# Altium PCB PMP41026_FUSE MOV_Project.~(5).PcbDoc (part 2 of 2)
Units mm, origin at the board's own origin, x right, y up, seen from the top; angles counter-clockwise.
Board outline 26.25 x 35 mm, 2 copper layers (Top Layer, Bottom Layer), stack 1.575 mm thick; 11 components, 9 nets, 22 pads, 48 vias.
Unrouted connection lines stored in the file: 1.

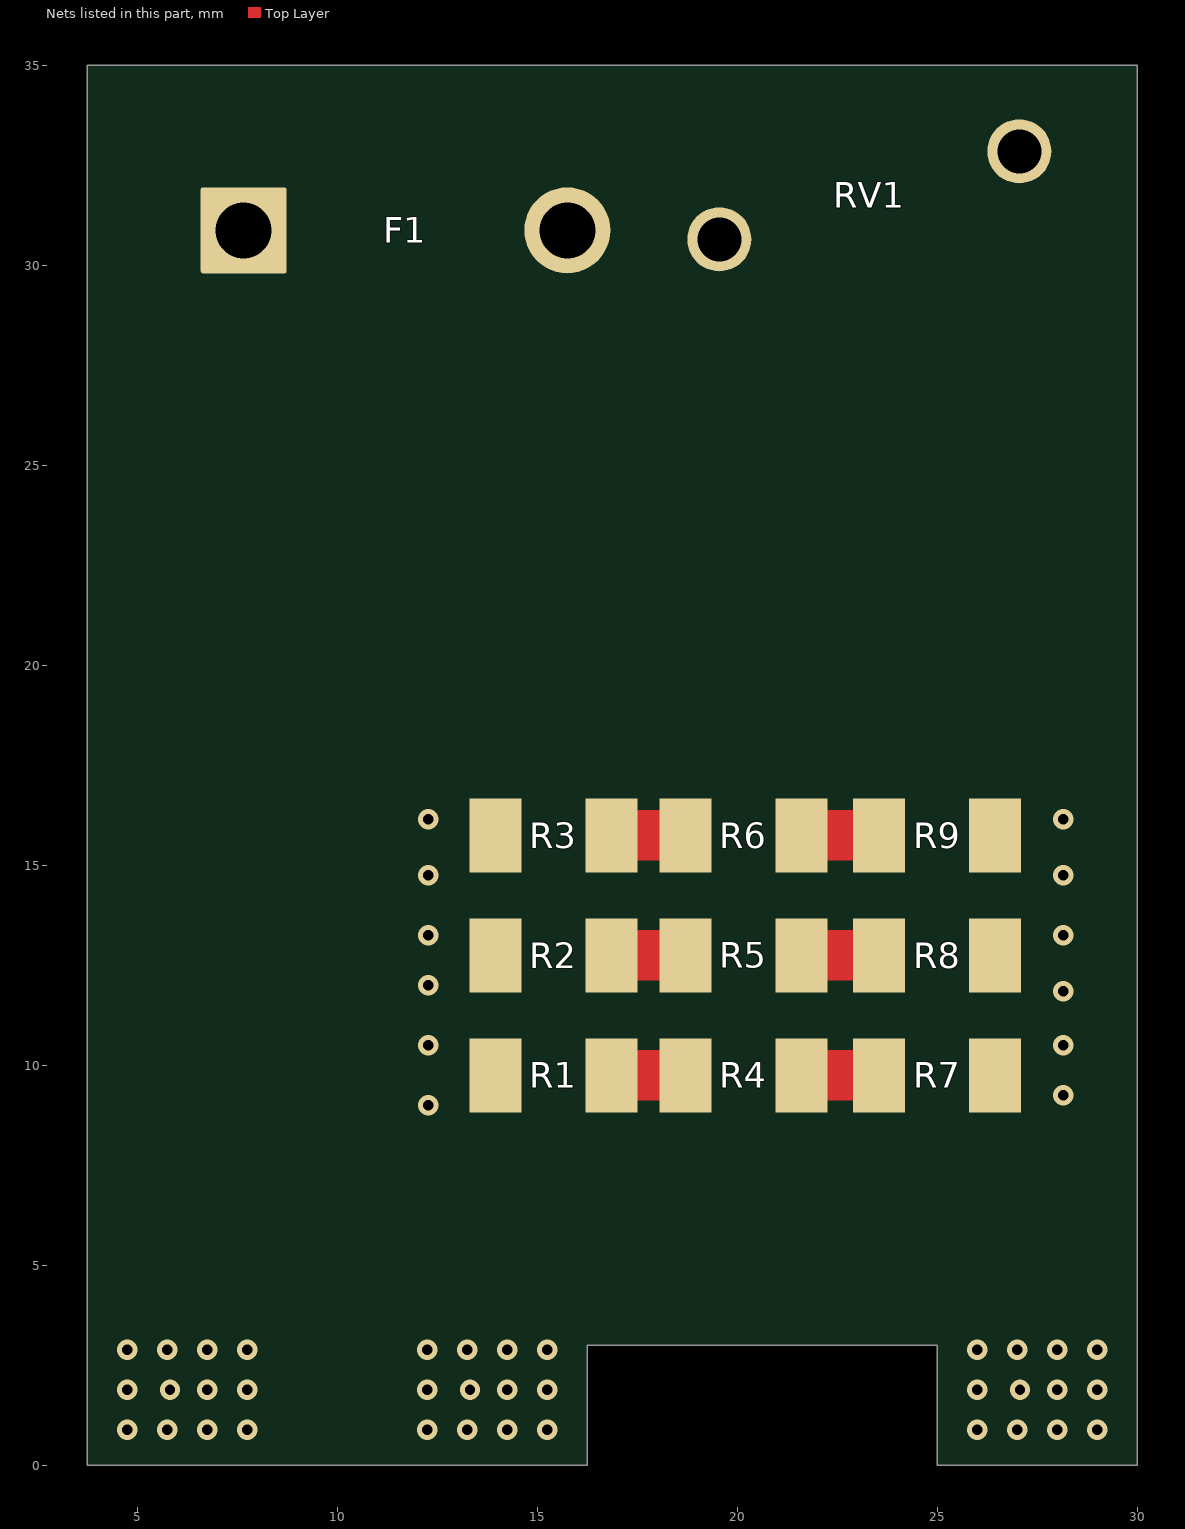
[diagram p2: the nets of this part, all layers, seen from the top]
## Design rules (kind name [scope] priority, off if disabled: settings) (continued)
PolygonConnect PolygonConnect_37 [All vs IsNamedPolygon('SGND') Or  IsNamedPolygon('SWNODE4') Or  IsNamedPolygon('5Vp') Or  IsNamedPolygon('SWNODE4') Or  IsNamedPolygon('VBB') Or  IsNamedPolygon('Line') Or  IsNamedPolygon('SGND') Or  IsNamedPolygon('SIGNAL_LAYER_2_C102_1_P032') Or  IsNamedPolygon('TOP_LAYER_54V2_P048') Or  IsNamedPolygon('ZCD') Or  IsNamedPolygon('PGND') Or  IsNamedPolygon('SIGNAL_LAYER_2_VBB_P094') Or  IsNamedPolygon('Line') Or  IsNamedPolygon('Line') Or  IsNamedPolygon('D404_2') Or  IsNamedPolygon('PGND') Or  IsNamedPolygon('SIGNAL_LAYER_1_ZCD_P108') Or  IsNamedPolygon('SWNODE3') Or  IsNamedPolygon('SIGNAL_LAYER_4_C102_1_P038') Or  IsNamedPolygon('SWNODE3') Or  IsNamedPolygon('LEG4_HS_DRV') Or  IsNamedPolygon('SWNODE4') Or  IsNamedPolygon('5Vs') Or  IsNamedPolygon('VBB') Or  IsNamedPolygon('TOP_LAYER_54V2_P048') Or  IsNamedPolygon('C102_1') Or  IsNamedPolygon('LEG4_LS_DRV') Or  IsNamedPolygon('T200_4') Or  IsNamedPolygon('SWNODE3') Or  IsNamedPolygon('Line') Or  IsNamedPolygon('SGND') Or  IsNamedPolygon('SGND') Or  IsNamedPolygon('SWNODE4') Or  IsNamedPolygon('12Vp') Or  IsNamedPolygon('BOTTOM_LAYER_NETC106_2_P030') Or  IsNamedPolygon('T200_4') Or  IsNamedPolygon('Vbulk1') Or  IsNamedPolygon('C108_1') Or  IsNamedPolygon('BOTTOM_LAYER_54V1_P128') Or  IsNamedPolygon('BOTTOM_LAYER_54V1_P128') Or  IsNamedPolygon('SWNODE') Or  IsNamedPolygon('Iout_SNS') Or  IsNamedPolygon('VSR') Or  IsNamedPolygon('D400_2') Or  IsNamedPolygon('D403_2') Or  IsNamedPolygon('SWNODE3') Or  IsNamedPolygon('T200_6') Or  IsNamedPolygon('SWNODE3') Or  IsNamedPolygon('C108_1') Or  IsNamedPolygon('PGND') Or  IsNamedPolygon('BOTTOM_LAYER_VBULK1_P096') Or  IsNamedPolygon('BOTTOM_LAYER_54V1_P128') Or  IsNamedPolygon('TOP_LAYER_12VS_P126') Or  IsNamedPolygon('SIGNAL_LAYER_1_VBULK1_P106') Or  IsNamedPolygon('T200_4') Or  IsNamedPolygon('SGND') Or  IsNamedPolygon('C108_1') Or  IsNamedPolygon('SWNODE3') Or  IsNamedPolygon('T200_6') Or  IsNamedPolygon('T200_6') Or  IsNamedPolygon('T200_6') Or  IsNamedPolygon('SGND') Or  IsNamedPolygon('C108_1') Or  IsNamedPolygon('SGND') Or  IsNamedPolygon('VBB') Or  IsNamedPolygon('T200_4') Or  IsNamedPolygon('LEG3_HS_DRV') Or  IsNamedPolygon('C108_1') Or  IsNamedPolygon('D403_2') Or  IsNamedPolygon('Iout_SNS') Or  IsNamedPolygon('C108_1') Or  IsNamedPolygon('SWNODE4')] p23: connectstyle=Direct reliefconductorwidth=0.254 reliefentries=4 polygonreliefangle="90 Angle" airgapwidth=0.254
PolygonConnect PolygonConnect_36 [All vs IsNamedPolygon('PGND') Or  IsNamedPolygon('BOTTOM_LAYER_54V1_P128') Or  IsNamedPolygon('SGND') Or  IsNamedPolygon('LEG4_LS_DRV') Or  IsNamedPolygon('TOP_LAYER_12VS_P126') Or  IsNamedPolygon('LEG4_HS_DRV') Or  IsNamedPolygon('LEG3_HS_DRV') Or  IsNamedPolygon('SGND') Or  IsNamedPolygon('C108_1') Or  IsNamedPolygon('12Vp') Or  IsNamedPolygon('D403_2') Or  IsNamedPolygon('SIGNAL_LAYER_1_ZCD_P108') Or  IsNamedPolygon('C108_1') Or  IsNamedPolygon('BOTTOM_LAYER_VBULK1_P096') Or  IsNamedPolygon('SWNODE') Or  IsNamedPolygon('T200_4') Or  IsNamedPolygon('D400_2') Or  IsNamedPolygon('C102_1') Or  IsNamedPolygon('Line') Or  IsNamedPolygon('VBB') Or  IsNamedPolygon('Line') Or  IsNamedPolygon('TOP_LAYER_54V2_P048') Or  IsNamedPolygon('BOTTOM_LAYER_NETC106_2_P030') Or  IsNamedPolygon('SIGNAL_LAYER_1_VBULK1_P106') Or  IsNamedPolygon('Line') Or  IsNamedPolygon('5Vp') Or  IsNamedPolygon('BOTTOM_LAYER_54V1_P128') Or  IsNamedPolygon('D404_2') Or  IsNamedPolygon('C108_1') Or  IsNamedPolygon('VSR') Or  IsNamedPolygon('T200_6') Or  IsNamedPolygon('VBB') Or  IsNamedPolygon('C108_1') Or  IsNamedPolygon('SIGNAL_LAYER_2_C102_1_P032') Or  IsNamedPolygon('SGND') Or  IsNamedPolygon('PGND') Or  IsNamedPolygon('SIGNAL_LAYER_4_C102_1_P038') Or  IsNamedPolygon('Vbulk1') Or  IsNamedPolygon('TOP_LAYER_54V2_P048') Or  IsNamedPolygon('Iout_SNS') Or  IsNamedPolygon('PGND') Or  IsNamedPolygon('T200_4') Or  IsNamedPolygon('ZCD') Or  IsNamedPolygon('Line') Or  IsNamedPolygon('C108_1') Or  IsNamedPolygon('D403_2') Or  IsNamedPolygon('SIGNAL_LAYER_2_VBB_P094') Or  IsNamedPolygon('SGND') Or  IsNamedPolygon('C108_1') Or  IsNamedPolygon('SIGNAL_LAYER_1_IOUT_SNS_P044') Or  IsNamedPolygon('BOTTOM_LAYER_54V1_P128') Or  IsNamedPolygon('T200_6')] p24: connectstyle=Direct reliefconductorwidth=0.254 reliefentries=4 polygonreliefangle="90 Angle" airgapwidth=0.254
PolygonConnect PolygonConnect_35 [All vs IsNamedPolygon('SWNODE') Or  IsNamedPolygon('D403_2') Or  IsNamedPolygon('D403_2') Or  IsNamedPolygon('PGND') Or  IsNamedPolygon('BOTTOM_LAYER_NETC106_2_P030') Or  IsNamedPolygon('SIGNAL_LAYER_2_C102_1_P032') Or  IsNamedPolygon('C102_1') Or  IsNamedPolygon('SIGNAL_LAYER_4_C102_1_P038') Or  IsNamedPolygon('SGND') Or  IsNamedPolygon('SIGNAL_LAYER_1_IOUT_SNS_P044') Or  IsNamedPolygon('BOTTOM_LAYER_54V1_P128') Or  IsNamedPolygon('TOP_LAYER_54V2_P048') Or  IsNamedPolygon('BOTTOM_LAYER_54V1_P128') Or  IsNamedPolygon('TOP_LAYER_54V2_P048') Or  IsNamedPolygon('C108_1') Or  IsNamedPolygon('C108_1') Or  IsNamedPolygon('C108_1') Or  IsNamedPolygon('C108_1') Or  IsNamedPolygon('C108_1') Or  IsNamedPolygon('C108_1') Or  IsNamedPolygon('PGND') Or  IsNamedPolygon('ZCD') Or  IsNamedPolygon('Line') Or  IsNamedPolygon('5Vp') Or  IsNamedPolygon('12Vp') Or  IsNamedPolygon('T200_4') Or  IsNamedPolygon('T200_6') Or  IsNamedPolygon('SGND') Or  IsNamedPolygon('T200_4') Or  IsNamedPolygon('T200_6') Or  IsNamedPolygon('SGND') Or  IsNamedPolygon('VSR') Or  IsNamedPolygon('Iout_SNS') Or  IsNamedPolygon('SIGNAL_LAYER_2_VBB_P094') Or  IsNamedPolygon('BOTTOM_LAYER_VBULK1_P096') Or  IsNamedPolygon('Vbulk1') Or  IsNamedPolygon('VBB') Or  IsNamedPolygon('SIGNAL_LAYER_1_VBULK1_P106') Or  IsNamedPolygon('SIGNAL_LAYER_1_ZCD_P108') Or  IsNamedPolygon('Line') Or  IsNamedPolygon('Line') Or  IsNamedPolygon('Line') Or  IsNamedPolygon('D404_2') Or  IsNamedPolygon('VBB') Or  IsNamedPolygon('D400_2') Or  IsNamedPolygon('SGND') Or  IsNamedPolygon('PGND') Or  IsNamedPolygon('TOP_LAYER_12VS_P126') Or  IsNamedPolygon('BOTTOM_LAYER_54V1_P128') Or  IsNamedPolygon('LEG3_HS_DRV')] p25: connectstyle=Direct reliefconductorwidth=0.254 reliefentries=4 polygonreliefangle="90 Angle" airgapwidth=0.254
PolygonConnect PolygonConnect_34 [All vs IsNamedPolygon('SWNODE') Or  IsNamedPolygon('D403_2') Or  IsNamedPolygon('D403_2') Or  IsNamedPolygon('PGND') Or  IsNamedPolygon('BOTTOM_LAYER_NETC106_2_P030') Or  IsNamedPolygon('SIGNAL_LAYER_2_C102_1_P032') Or  IsNamedPolygon('C102_1') Or  IsNamedPolygon('SIGNAL_LAYER_4_C102_1_P038') Or  IsNamedPolygon('SGND') Or  IsNamedPolygon('SIGNAL_LAYER_1_IOUT_SNS_P044') Or  IsNamedPolygon('BOTTOM_LAYER_54V1_P128') Or  IsNamedPolygon('TOP_LAYER_54V2_P048') Or  IsNamedPolygon('BOTTOM_LAYER_54V1_P128') Or  IsNamedPolygon('TOP_LAYER_54V2_P048') Or  IsNamedPolygon('C108_1') Or  IsNamedPolygon('C108_1') Or  IsNamedPolygon('C108_1') Or  IsNamedPolygon('C108_1') Or  IsNamedPolygon('C108_1') Or  IsNamedPolygon('C108_1') Or  IsNamedPolygon('PGND') Or  IsNamedPolygon('ZCD') Or  IsNamedPolygon('Line') Or  IsNamedPolygon('5Vp') Or  IsNamedPolygon('12Vp') Or  IsNamedPolygon('T200_4') Or  IsNamedPolygon('T200_6') Or  IsNamedPolygon('SGND') Or  IsNamedPolygon('T200_4') Or  IsNamedPolygon('T200_6') Or  IsNamedPolygon('SGND') Or  IsNamedPolygon('VSR') Or  IsNamedPolygon('Iout_SNS') Or  IsNamedPolygon('SIGNAL_LAYER_2_VBB_P094') Or  IsNamedPolygon('BOTTOM_LAYER_VBULK1_P096') Or  IsNamedPolygon('Vbulk1') Or  IsNamedPolygon('VBB') Or  IsNamedPolygon('SIGNAL_LAYER_1_VBULK1_P106') Or  IsNamedPolygon('SIGNAL_LAYER_1_ZCD_P108') Or  IsNamedPolygon('Line') Or  IsNamedPolygon('Line') Or  IsNamedPolygon('Line') Or  IsNamedPolygon('D404_2') Or  IsNamedPolygon('VBB') Or  IsNamedPolygon('D400_2') Or  IsNamedPolygon('SGND')] p26: connectstyle=Direct reliefconductorwidth=0.254 reliefentries=4 polygonreliefangle="90 Angle" airgapwidth=0.254
PolygonConnect PolygonConnect_33 [All vs IsNamedPolygon('SIGNAL_LAYER_1_VBULK1_P106')] p27: connectstyle=Direct reliefconductorwidth=0.254 reliefentries=4 polygonreliefangle="90 Angle" airgapwidth=0.254
PolygonConnect PolygonConnect_32 [All vs IsNamedPolygon('SIGNAL_LAYER_1_VBULK1_P106')] p28: connectstyle=Direct reliefconductorwidth=0.254 reliefentries=4 polygonreliefangle="90 Angle" airgapwidth=0.254
PolygonConnect PolygonConnect_31 [All vs IsNamedPolygon('SIGNAL_LAYER_1_VBULK1_P106')] p29: connectstyle=Direct reliefconductorwidth=0.254 reliefentries=4 polygonreliefangle="90 Angle" airgapwidth=0.254
PolygonConnect PolygonConnect_30 [All vs IsNamedPolygon('VBB')] p30: connectstyle=Direct reliefconductorwidth=0.254 reliefentries=4 polygonreliefangle="90 Angle" airgapwidth=0.254
PolygonConnect PolygonConnect_29 [All vs IsNamedPolygon('SGND')] p31: connectstyle=Direct reliefconductorwidth=0.254 reliefentries=4 polygonreliefangle="90 Angle" airgapwidth=0.254
PolygonConnect PolygonConnect_28 [All vs IsNamedPolygon('Vbulk1')] p32: connectstyle=Direct reliefconductorwidth=0.254 reliefentries=4 polygonreliefangle="90 Angle" airgapwidth=0.254
PolygonConnect PolygonConnect_27 [All vs IsNamedPolygon('BOTTOM_LAYER_VBULK1_P096')] p33: connectstyle=Direct reliefconductorwidth=0.254 reliefentries=4 polygonreliefangle="90 Angle" airgapwidth=0.254
PolygonConnect PolygonConnect_26 [All vs IsNamedPolygon('SIGNAL_LAYER_2_VBB_P094')] p34: connectstyle=Direct reliefconductorwidth=0.254 reliefentries=4 polygonreliefangle="90 Angle" airgapwidth=0.254
PolygonConnect PolygonConnect_25 [All vs IsNamedPolygon('C108_1')] p35: connectstyle=Direct reliefconductorwidth=0.254 reliefentries=4 polygonreliefangle="90 Angle" airgapwidth=0.254
PolygonConnect PolygonConnect_24 [All vs IsNamedPolygon('BOTTOM_LAYER_EARTH_P100')] p36: connectstyle=Direct reliefconductorwidth=0.254 reliefentries=4 polygonreliefangle="90 Angle" airgapwidth=0.254
PolygonConnect PolygonConnect_23 [All vs IsNamedPolygon('BOTTOM_LAYER_54V1_P128')] p37: connectstyle=Direct reliefconductorwidth=0.254 reliefentries=4 polygonreliefangle="90 Angle" airgapwidth=0.254
PolygonConnect PolygonConnect_22 [All vs IsNamedPolygon('BOTTOM_LAYER_VBULK1_P096')] p38: connectstyle=Direct reliefconductorwidth=0.254 reliefentries=4 polygonreliefangle="90 Angle" airgapwidth=0.254
PolygonConnect PolygonConnect_21 [All vs IsNamedPolygon('SIGNAL_LAYER_2_VBB_P094')] p39: connectstyle=Direct reliefconductorwidth=0.254 reliefentries=4 polygonreliefangle="90 Angle" airgapwidth=0.254
PolygonConnect PolygonConnect_20 [All vs IsNamedPolygon('Iout_SNS')] p40: connectstyle=Direct reliefconductorwidth=0.254 reliefentries=4 polygonreliefangle="90 Angle" airgapwidth=0.254
PolygonConnect PolygonConnect_19 [All vs IsNamedPolygon('C108_1') Or  IsNamedPolygon('BOTTOM_LAYER_NETC106_2_P030') Or  IsNamedPolygon('D403_2') Or  IsNamedPolygon('C102_1') Or  IsNamedPolygon('SWNODE') Or  IsNamedPolygon('D403_2') Or  IsNamedPolygon('SIGNAL_LAYER_4_C102_1_P038') Or  IsNamedPolygon('PGND') Or  IsNamedPolygon('SIGNAL_LAYER_2_C102_1_P032') Or  IsNamedPolygon('SIGNAL_LAYER_1_IOUT_SNS_P044') Or  IsNamedPolygon('SGND') Or  IsNamedPolygon('C108_1') Or  IsNamedPolygon('BOTTOM_LAYER_54V1_P128') Or  IsNamedPolygon('C108_1') Or  IsNamedPolygon('C108_1') Or  IsNamedPolygon('TOP_LAYER_54V2_P048') Or  IsNamedPolygon('BOTTOM_LAYER_54V1_P128') Or  IsNamedPolygon('TOP_LAYER_54V2_P048') Or  IsNamedPolygon('C108_1') Or  IsNamedPolygon('C108_1') Or  IsNamedPolygon('12Vp') Or  IsNamedPolygon('5Vp') Or  IsNamedPolygon('Line') Or  IsNamedPolygon('T200_4') Or  IsNamedPolygon('SGND') Or  IsNamedPolygon('VSR') Or  IsNamedPolygon('ZCD') Or  IsNamedPolygon('PGND') Or  IsNamedPolygon('T200_6') Or  IsNamedPolygon('Neutral') Or  IsNamedPolygon('T200_4') Or  IsNamedPolygon('SGND') Or  IsNamedPolygon('T200_6')] p41: connectstyle=Direct reliefconductorwidth=0.254 reliefentries=4 polygonreliefangle="90 Angle" airgapwidth=0.254
PolygonConnect PolygonConnect_18 [All vs IsNamedPolygon('SWNODE') Or  IsNamedPolygon('D403_2') Or  IsNamedPolygon('D403_2') Or  IsNamedPolygon('PGND') Or  IsNamedPolygon('BOTTOM_LAYER_NETC106_2_P030') Or  IsNamedPolygon('SIGNAL_LAYER_2_C102_1_P032') Or  IsNamedPolygon('C102_1') Or  IsNamedPolygon('SIGNAL_LAYER_4_C102_1_P038') Or  IsNamedPolygon('SGND') Or  IsNamedPolygon('SIGNAL_LAYER_1_IOUT_SNS_P044') Or  IsNamedPolygon('BOTTOM_LAYER_54V1_P128') Or  IsNamedPolygon('TOP_LAYER_54V2_P048') Or  IsNamedPolygon('BOTTOM_LAYER_54V1_P128') Or  IsNamedPolygon('TOP_LAYER_54V2_P048') Or  IsNamedPolygon('C108_1') Or  IsNamedPolygon('C108_1') Or  IsNamedPolygon('C108_1') Or  IsNamedPolygon('C108_1') Or  IsNamedPolygon('C108_1') Or  IsNamedPolygon('C108_1') Or  IsNamedPolygon('Neutral') Or  IsNamedPolygon('PGND') Or  IsNamedPolygon('ZCD') Or  IsNamedPolygon('Line') Or  IsNamedPolygon('5Vp') Or  IsNamedPolygon('12Vp') Or  IsNamedPolygon('T200_4') Or  IsNamedPolygon('T200_6') Or  IsNamedPolygon('SGND') Or  IsNamedPolygon('T200_4') Or  IsNamedPolygon('T200_6') Or  IsNamedPolygon('SGND')] p42: connectstyle=Direct reliefconductorwidth=0.254 reliefentries=4 polygonreliefangle="90 Angle" airgapwidth=0.254
PolygonConnect PolygonConnect_17 [All vs IsNamedPolygon('12Vp') Or  IsNamedPolygon('T200_4') Or  IsNamedPolygon('T200_6') Or  IsNamedPolygon('SGND') Or  IsNamedPolygon('TOP_LAYER_54V2_P048') Or  IsNamedPolygon('SIGNAL_LAYER_1_IOUT_SNS_P044') Or  IsNamedPolygon('BOTTOM_LAYER_54V1_P128') Or  IsNamedPolygon('SGND') Or  IsNamedPolygon('C102_1') Or  IsNamedPolygon('SIGNAL_LAYER_4_C102_1_P038') Or  IsNamedPolygon('Neutral') Or  IsNamedPolygon('C108_1') Or  IsNamedPolygon('C108_1') Or  IsNamedPolygon('C108_1') Or  IsNamedPolygon('BOTTOM_LAYER_54V1_P128') Or  IsNamedPolygon('TOP_LAYER_54V2_P048') Or  IsNamedPolygon('SIGNAL_LAYER_2_C102_1_P032') Or  IsNamedPolygon('SWNODE') Or  IsNamedPolygon('C108_1') Or  IsNamedPolygon('C108_1') Or  IsNamedPolygon('C108_1') Or  IsNamedPolygon('D403_2') Or  IsNamedPolygon('BOTTOM_LAYER_NETC106_2_P030') Or  IsNamedPolygon('PGND') Or  IsNamedPolygon('D403_2') Or  IsNamedPolygon('5Vp') Or  IsNamedPolygon('PGND') Or  IsNamedPolygon('ZCD') Or  IsNamedPolygon('Line')] p43: connectstyle=Direct reliefconductorwidth=0.254 reliefentries=4 polygonreliefangle="90 Angle" airgapwidth=0.254
PolygonConnect PolygonConnect_16 [All vs IsNamedPolygon('D403_2') Or  IsNamedPolygon('C102_1') Or  IsNamedPolygon('C108_1') Or  IsNamedPolygon('SWNODE') Or  IsNamedPolygon('BOTTOM_LAYER_54V1_P128') Or  IsNamedPolygon('SGND') Or  IsNamedPolygon('Line') Or  IsNamedPolygon('ZCD') Or  IsNamedPolygon('SIGNAL_LAYER_1_IOUT_SNS_P044') Or  IsNamedPolygon('Neutral') Or  IsNamedPolygon('PGND') Or  IsNamedPolygon('12Vp') Or  IsNamedPolygon('C108_1') Or  IsNamedPolygon('C108_1') Or  IsNamedPolygon('TOP_LAYER_54V2_P048') Or  IsNamedPolygon('C108_1') Or  IsNamedPolygon('TOP_LAYER_54V2_P048') Or  IsNamedPolygon('T200_4') Or  IsNamedPolygon('T200_6') Or  IsNamedPolygon('D403_2') Or  IsNamedPolygon('C108_1') Or  IsNamedPolygon('C108_1') Or  IsNamedPolygon('SIGNAL_LAYER_4_C102_1_P038') Or  IsNamedPolygon('SIGNAL_LAYER_2_C102_1_P032') Or  IsNamedPolygon('PGND') Or  IsNamedPolygon('BOTTOM_LAYER_NETC106_2_P030') Or  IsNamedPolygon('5Vp') Or  IsNamedPolygon('BOTTOM_LAYER_54V1_P128')] p44: connectstyle=Direct reliefconductorwidth=0.254 reliefentries=4 polygonreliefangle="90 Angle" airgapwidth=0.254
PolygonConnect PolygonConnect_15 [All vs IsNamedPolygon('SWNODE') Or  IsNamedPolygon('D403_2') Or  IsNamedPolygon('D403_2') Or  IsNamedPolygon('SIGNAL_LAYER_1_PGND_P018') Or  IsNamedPolygon('PGND') Or  IsNamedPolygon('BOTTOM_LAYER_NETC106_2_P030') Or  IsNamedPolygon('SIGNAL_LAYER_2_C102_1_P032') Or  IsNamedPolygon('C102_1') Or  IsNamedPolygon('SIGNAL_LAYER_4_C102_1_P038') Or  IsNamedPolygon('SGND') Or  IsNamedPolygon('SIGNAL_LAYER_1_IOUT_SNS_P044') Or  IsNamedPolygon('BOTTOM_LAYER_54V1_P128') Or  IsNamedPolygon('TOP_LAYER_54V2_P048') Or  IsNamedPolygon('BOTTOM_LAYER_54V1_P128') Or  IsNamedPolygon('TOP_LAYER_54V2_P048') Or  IsNamedPolygon('C108_1') Or  IsNamedPolygon('C108_1') Or  IsNamedPolygon('C108_1') Or  IsNamedPolygon('C108_1') Or  IsNamedPolygon('C108_1') Or  IsNamedPolygon('C108_1') Or  IsNamedPolygon('Neutral') Or  IsNamedPolygon('PGND') Or  IsNamedPolygon('ZCD') Or  IsNamedPolygon('Line') Or  IsNamedPolygon('5Vp') Or  IsNamedPolygon('12Vp')] p45: connectstyle=Direct reliefconductorwidth=0.254 reliefentries=4 polygonreliefangle="90 Angle" airgapwidth=0.254
PolygonConnect PolygonConnect_14 [All vs IsNamedPolygon('TOP_LAYER_54V2_P048') Or  IsNamedPolygon('C108_1') Or  IsNamedPolygon('C108_1') Or  IsNamedPolygon('SIGNAL_LAYER_4_C102_1_P038') Or  IsNamedPolygon('C102_1') Or  IsNamedPolygon('SIGNAL_LAYER_2_C102_1_P032') Or  IsNamedPolygon('SIGNAL_LAYER_1_PGND_P018') Or  IsNamedPolygon('SIGNAL_LAYER_1_IOUT_SNS_P044') Or  IsNamedPolygon('SGND') Or  IsNamedPolygon('C108_1') Or  IsNamedPolygon('ZCD') Or  IsNamedPolygon('PGND') Or  IsNamedPolygon('TOP_LAYER_54V2_P048') Or  IsNamedPolygon('BOTTOM_LAYER_NETC106_2_P030') Or  IsNamedPolygon('PGND') Or  IsNamedPolygon('C108_1') Or  IsNamedPolygon('C108_1') Or  IsNamedPolygon('D403_2') Or  IsNamedPolygon('Line') Or  IsNamedPolygon('C108_1') Or  IsNamedPolygon('Neutral') Or  IsNamedPolygon('SWNODE') Or  IsNamedPolygon('D403_2') Or  IsNamedPolygon('BOTTOM_LAYER_54V1_P128') Or  IsNamedPolygon('BOTTOM_LAYER_54V1_P128')] p46: connectstyle=Direct reliefconductorwidth=0.254 reliefentries=4 polygonreliefangle="90 Angle" airgapwidth=0.254
PolygonConnect PolygonConnect_13 [All vs IsNamedPolygon('PGND') Or  IsNamedPolygon('D403_2') Or  IsNamedPolygon('SIGNAL_LAYER_1_PGND_P018') Or  IsNamedPolygon('D403_2') Or  IsNamedPolygon('SWNODE') Or  IsNamedPolygon('SGND') Or  IsNamedPolygon('BOTTOM_LAYER_54V1_P128') Or  IsNamedPolygon('C108_1') Or  IsNamedPolygon('SIGNAL_LAYER_4_C102_1_P038') Or  IsNamedPolygon('C108_1') Or  IsNamedPolygon('TOP_LAYER_54V2_P048') Or  IsNamedPolygon('TOP_LAYER_54V2_P048') Or  IsNamedPolygon('C108_1') Or  IsNamedPolygon('C108_1') Or  IsNamedPolygon('C108_1') Or  IsNamedPolygon('BOTTOM_LAYER_NETC106_2_P030') Or  IsNamedPolygon('SIGNAL_LAYER_1_IOUT_SNS_P044') Or  IsNamedPolygon('C108_1') Or  IsNamedPolygon('C102_1') Or  IsNamedPolygon('SIGNAL_LAYER_2_C102_1_P032') Or  IsNamedPolygon('BOTTOM_LAYER_54V1_P128')] p47: connectstyle=Direct reliefconductorwidth=0.254 reliefentries=4 polygonreliefangle="90 Angle" airgapwidth=0.254
PolygonConnect PolygonConnect_12 [All vs IsNamedPolygon('TOP_LAYER_54V2_P048')] p48: connectstyle=Direct reliefconductorwidth=0.254 reliefentries=4 polygonreliefangle="90 Angle" airgapwidth=0.254
PolygonConnect PolygonConnect_11 [All vs IsNamedPolygon('BOTTOM_LAYER_54V1_P128')] p49: connectstyle=Direct reliefconductorwidth=0.254 reliefentries=4 polygonreliefangle="90 Angle" airgapwidth=0.254
PolygonConnect PolygonConnect_10 [All vs IsNamedPolygon('SIGNAL_LAYER_1_IOUT_SNS_P044')] p50: thpad.connectstyle=Direct thpad.reliefconductorwidth=0.254 thpad.reliefentries=4 thpad.polygonreliefangle="90 Angle" thpad.airgapwidth=0.254 smdpad.connectstyle=Relief smdpad.reliefconductorwidth=0.254 smdpad.reliefentries=4 smdpad.polygonreliefangle="90 Angle" smdpad.airgapwidth=0.254 via.connectstyle=Direct via.reliefconductorwidth=0.254 via.reliefentries=4 via.polygonreliefangle="90 Angle" via.airgapwidth=0.254
PolygonConnect PolygonConnect_9 [All vs IsNamedPolygon('SGND')] p51: thpad.connectstyle=Direct thpad.reliefconductorwidth=0.254 thpad.reliefentries=4 thpad.polygonreliefangle="90 Angle" thpad.airgapwidth=0.254 smdpad.connectstyle=Relief smdpad.reliefconductorwidth=0.254 smdpad.reliefentries=4 smdpad.polygonreliefangle="90 Angle" smdpad.airgapwidth=0.254 via.connectstyle=Direct via.reliefconductorwidth=0.254 via.reliefentries=4 via.polygonreliefangle="90 Angle" via.airgapwidth=0.254
PolygonConnect PolygonConnect_8 [All vs IsNamedPolygon('SGND')] p52: thpad.connectstyle=Direct thpad.reliefconductorwidth=0.254 thpad.reliefentries=4 thpad.polygonreliefangle="90 Angle" thpad.airgapwidth=0.254 smdpad.connectstyle=Relief smdpad.reliefconductorwidth=0.254 smdpad.reliefentries=4 smdpad.polygonreliefangle="90 Angle" smdpad.airgapwidth=0.254 via.connectstyle=Direct via.reliefconductorwidth=0.254 via.reliefentries=4 via.polygonreliefangle="90 Angle" via.airgapwidth=0.254
PolygonConnect PolygonConnect_7 [All vs IsNamedPolygon('SGND')] p53: thpad.connectstyle=Relief thpad.reliefconductorwidth=0 thpad.reliefentries=4 thpad.polygonreliefangle="90 Angle" thpad.airgapwidth=0 smdpad.connectstyle=Relief smdpad.reliefconductorwidth=0.254 smdpad.reliefentries=4 smdpad.polygonreliefangle="90 Angle" smdpad.airgapwidth=0.254 via.connectstyle=Relief via.reliefconductorwidth=0.254 via.reliefentries=4 via.polygonreliefangle="90 Angle" via.airgapwidth=0.254
PolygonConnect PolygonConnect_6 [All vs IsNamedPolygon('SGND')] p54: thpad.connectstyle=Direct thpad.reliefconductorwidth=0.254 thpad.reliefentries=4 thpad.polygonreliefangle="90 Angle" thpad.airgapwidth=0.254 smdpad.connectstyle=Relief smdpad.reliefconductorwidth=0.254 smdpad.reliefentries=4 smdpad.polygonreliefangle="90 Angle" smdpad.airgapwidth=0.254 via.connectstyle=Relief via.reliefconductorwidth=0.254 via.reliefentries=4 via.polygonreliefangle="90 Angle" via.airgapwidth=0.254
PolygonConnect PolygonConnect_5 [All vs IsNamedPolygon('SGND')] p55: thpad.connectstyle=Direct thpad.reliefconductorwidth=0.254 thpad.reliefentries=4 thpad.polygonreliefangle="90 Angle" thpad.airgapwidth=0.254 smdpad.connectstyle=Relief smdpad.reliefconductorwidth=0.254 smdpad.reliefentries=4 smdpad.polygonreliefangle="90 Angle" smdpad.airgapwidth=0.254 via.connectstyle=Relief via.reliefconductorwidth=0.254 via.reliefentries=4 via.polygonreliefangle="90 Angle" via.airgapwidth=0.254
PolygonConnect PolygonConnect_4 [All vs IsNamedPolygon('SIGNAL_LAYER_1_PGND_P018') Or  IsNamedPolygon('SWNODE') Or  IsNamedPolygon('D403_2') Or  IsNamedPolygon('SIGNAL_LAYER_4_C102_1_P038') Or  IsNamedPolygon('D403_2') Or  IsNamedPolygon('BOTTOM_LAYER_NETC106_2_P030') Or  IsNamedPolygon('C102_1') Or  IsNamedPolygon('PGND') Or  IsNamedPolygon('SIGNAL_LAYER_2_C102_1_P032')] p56: connectstyle=Direct reliefconductorwidth=0.254 reliefentries=4 polygonreliefangle="90 Angle" airgapwidth=0.254
PolygonConnect PolygonConnect_3 [All vs IsNamedPolygon('SWNODE') Or  IsNamedPolygon('D403_2') Or  IsNamedPolygon('Neutral') Or  IsNamedPolygon('C106_2') Or  IsNamedPolygon('D403_2') Or  IsNamedPolygon('Neutral') Or  IsNamedPolygon('Neutral')] p57: connectstyle=Direct reliefconductorwidth=0.254 reliefentries=4 polygonreliefangle="90 Angle" airgapwidth=0.254
PolygonConnect PolygonConnect_2 [All vs IsNamedPolygon('Neutral') Or  IsNamedPolygon('Neutral') Or  IsNamedPolygon('C106_2') Or  IsNamedPolygon('SWNODE') Or  IsNamedPolygon('Neutral')] p58: connectstyle=Direct reliefconductorwidth=0.254 reliefentries=4 polygonreliefangle="90 Angle" airgapwidth=0.254
PolygonConnect PolygonConnect_1 [All vs IsNamedPolygon('Neutral') Or  IsNamedPolygon('Neutral')] p59: connectstyle=Direct reliefconductorwidth=0.254 reliefentries=4 polygonreliefangle="90 Angle" airgapwidth=0.254
PolygonConnect [All] p60: connectstyle=Direct reliefconductorwidth=0.254 reliefentries=4 polygonreliefangle="90 Angle" airgapwidth=0.254
RoutingVias ThermalPadVias [IsVia and InAnyComponent] p1: holewidth=0.2 width=0.5 viastyle="Through Hole" minholewidth=0.2 minwidth=0.5 maxholewidth=0.33 maxwidth=0.6
RoutingVias [All] p2: holewidth=0.406 width=0.864 viastyle="Through Hole" minholewidth=0.2 minwidth=0.508 maxholewidth=1.016 maxwidth=1.651
SilkToBoardRegionClearance [Not ((IsComment or IsDesignator) And (Hide <> 'False')) and not InRegion(1000,500,4000,800)] p1:
SilkToSilkClearance SilkToSilkClearance_Pb-FreeLogo [(HasFootprint('Pb-Free_Overlay_Medium') OR HasFootprint('Pb-Free_Overlay_Small')) vs (HasFootprint('Pb-Free_Overlay_Medium') OR HasFootprint('Pb-Free_Overlay_Small'))] p1: silktosilkclearance=0
SilkToSilkClearance [All] p2: silktosilkclearance=0.102
SilkToSolderMaskClearance SilkToComponentPadClearance [(IsPad or IsFill or IsRegion) and InAnycomponent] p1: minsilkscreentomaskgap=0.127 clearancetoexposedcopper=TRUE
SilkToSolderMaskClearance "Silk to Solder Mask Opening" [All] p2: minsilkscreentomaskgap=0.102 clearancetoexposedcopper=FALSE
SolderMaskExpansion [All] p1: expansion=0.05
Width [All] p1: maxlimit=2.54 minlimit=0.152 preferedwidth=0.254 checkconnectedcopper=TRUE
13 further rules are at their usual default settings.

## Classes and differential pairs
net class N: N
net class L: Lout N

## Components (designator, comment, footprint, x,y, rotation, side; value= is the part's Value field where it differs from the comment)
F1 "0525025.MXEP_vm" FP-0525025.MXEP_vm_AXIAL-MFG 7.658,30.875 r0 bottom
R1 "CRCW1206330KJNEA" 1206 15.4,9.75 r180 top value=330k
R2 "CRCW1206330KJNEA" 1206 15.4,12.75 r180 top value=330k
R3 "CRCW1206330KJNEA" 1206 15.4,15.75 r180 top value=330k
R4 "CRCW1206330KJNEA" 1206 20.15,9.75 r180 top value=330k
R5 "CRCW1206330KJNEA" 1206 20.15,12.75 r180 top value=330k
R6 "CRCW1206330KJNEA" 1206 20.15,15.75 r180 top value=330k
R7 "CRCW1206330KJNEA" 1206 24.993,9.75 r180 top value=330k
R8 "CRCW1206330KJNEA" 1206 24.993,12.75 r180 top value=330k
R9 "CRCW1206330KJNEA" 1206 24.993,15.75 r180 top value=330k
RV1 "S10K275E2" VAR_S10K275E2 23.3,31.75 r0 bottom value=275V

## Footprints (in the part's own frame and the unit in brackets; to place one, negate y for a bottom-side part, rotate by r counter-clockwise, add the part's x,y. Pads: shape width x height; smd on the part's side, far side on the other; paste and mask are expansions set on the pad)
1206 [mm] "1206 from SM-752 data"
  rect 1.3x1.85 smd: 1(-1.45,0) 2(1.45,0)
  silkscreen extent -2.4,-1.21 2.4,1.21, body extent -1.7,-0.9 1.7,0.9, height 1.35
FP-0525025.MXEP_vm_AXIAL-MFG [mm]
  rrect5% 2.15x2.15 hole 1.4 paste-1000 mask+0: 1(0,0)
  round 2.15 hole 1.4 paste-1000 mask+0: 2(8.092,0)
  silkscreen extent -3.64,-3.64 3.64,3.64, body extent -3.49,-3.49 8.69,3.49, height 34.52
VAR_S10K275E2 [mm] "EPCOS"
  round 1.6 hole 1.1: 1(-3.75,1.1) 2(3.75,-1.1)
  silkscreen extent -6,-2.7 6,2.7, body extent -6.02,-2.7 5.98,2.7, height 15

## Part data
F1: library part CMP-4956-0000-1, "25A AC 450V DC Fuse Cartridge, Ceramic Through Hole 3AB, 3AG, 1/4\" x 1-1/4\" (Axial)", Digikey Part Number=F10249-ND, Fuse Current=25A, Fuse Interrupt Dc Current=10000A, Manufacturer=Littelfuse, Mouser Part Number=576-0525025.MXEP, Operating Temperature Range="-55°C to +125°C"
R1 R2 R3 R4 R5 R6 R7 R8 R9: library part CMP-0018656-3, "RES, 330 k, 5%, 0.25 W, AEC-Q200 Grade 0, 1206", Manufacturer=Vishay-Dale, Power_W=250mW, Supplier Part Number 1=541-330KECT-ND, TempCo="200 ppm/C", Tolerance_%=5%, Value2=0.25W, Value_Code=330k
RV1: library part CMP-0002100-2, "Varistor 275V RMS 10MM Radial, TH", Manufacturer=TDK, Supplier Part Number 1=495-1433-ND

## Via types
v1: diameter 0.508, hole 0.254, Top Layer to Bottom Layer, 48 vias

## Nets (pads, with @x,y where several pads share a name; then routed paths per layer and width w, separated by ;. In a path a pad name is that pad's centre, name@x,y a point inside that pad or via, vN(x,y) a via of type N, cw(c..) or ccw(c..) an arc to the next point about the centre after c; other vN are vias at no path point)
Lin: F1.1
  other v1: 4.75,0.891 5.75,0.891 6.75,0.891 7.75,0.891 4.75,1.891 5.815,1.891 6.75,1.891 7.75,1.891 4.75,2.891 5.75,2.891 6.75,2.891 7.75,2.891
Lout: F1.2 R1.2 R2.2 R3.2 RV1.1
  other v1: 12.25,0.891 13.25,0.891 14.25,0.891 15.25,0.891 12.25,1.891 13.315,1.891 14.25,1.891 15.25,1.891 12.25,2.891 13.25,2.891 14.25,2.891 15.25,2.891 12.275,9 12.275,10.5 12.275,12 12.275,13.25 12.275,14.75 12.275,16.15
N: R7.1 R8.1 R9.1 RV1.2
  other v1: 26,0.891 27,0.891 28,0.891 29,0.891 26,1.891 27.065,1.891 28,1.891 29,1.891 26,2.891 27,2.891 28,2.891 29,2.891 28.15,9.25 28.15,10.5 28.15,11.85 28.15,13.25 28.15,14.75 28.15,16.15
NetR1_1: R1.1 R4.2 | length 1.9
  Top Layer w1.27: R1.1@16.85,9.75 R4.2@18.7,9.75
NetR2_1: R2.1 R5.2 | length 1.9
  Top Layer w1.27: R2.1@16.85,12.75 R5.2@18.7,12.75
NetR3_1: R3.1 R6.2 | length 1.9
  Top Layer w1.27: R3.1@16.85,15.75 R6.2@18.7,15.75
NetR4_1: R4.1 R7.2 | length 1.9
  Top Layer w1.27: R4.1@21.6,9.75 R7.2@23.543,9.75
NetR5_1: R5.1 R8.2 | length 1.9
  Top Layer w1.27: R5.1@21.6,12.75 R8.2@23.543,12.75
NetR6_1: R6.1 R9.2 | length 1.9
  Top Layer w1.27: R6.1@21.6,15.75 R9.2@23.543,15.75

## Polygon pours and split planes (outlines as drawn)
Lout on Bottom Layer "BOTTOM_LAYER_LOUT_P012" (solid, remove dead copper, pour order 12): 18.25,5.568 20.75,8.068 20.75,34.5 20.5,34.75 14.5,34.75 13.5,33.75 11.25,31.5 11.25,3.75 16.25,3.75
Lin on Bottom Layer "BOTTOM_LAYER_LIN_P008" (solid, remove dead copper, pour order 8): 9.5,31.875 8.875,32.5 4.5,32.5 3.75,31.75 3.75,3.766 8.75,3.766 9.5,4.516
N on Bottom Layer "BOTTOM_LAYER_N_P004" (solid, remove dead copper, pour order 4): 25,3.75 25,17.75 25,32.707 25.992,33.7 28.8,33.7 29.75,32.75 29.75,4 30,3.75
Lout on Top Layer "TOP_LAYER_LOUT_P006" (solid, remove dead copper, pour order 6): 18.25,20.033 15.908,17.691 15.908,9.402 17.5,7.809 17.5,5 16.25,3.75 11.25,3.75 11.25,31.5 13.5,33.75 14.5,34.75 20.45,34.75 20.75,34.45 20.75,22.533
Lin on Top Layer "TOP_LAYER_LIN_P010" (solid, remove dead copper, pour order 10): 8.75,3.766 9.5,4.516 9.5,31.25 9.5,31.875 8.875,32.5 4.5,32.5 3.75,31.75 3.75,3.766
N on Top Layer "TOP_LAYER_N_P014" (solid, remove dead copper, pour order 14): 25,3.75 25,17.75 25,30.25 26.625,31.875 28.188,31.875 29.75,30.312 29.75,4 30,3.75

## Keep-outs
Keep-Out Layer:
  text ".Layer_Name" at 14.656,-21.806 h1.52

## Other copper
Top Layer:
  region net N: 29.9,3.75 29.9,0.1 25.1,0.1 25.1,3.75
  region net Lout: 16.25,3.75 16.25,0 11.25,0 11.25,3.75
  region net Lin: 8.75,3.766 8.75,0.016 3.75,0.016 3.75,3.766
  text ".Layer_Name" at 14.656,-21.806 h1.52
Bottom Layer:
  region net N: 29.9,3.75 29.9,0.1 25.1,0.1 25.1,3.75
  region net Lout: 16.25,3.75 16.25,0 11.25,0 11.25,3.75
  region net Lin: 8.75,3.766 8.75,0.016 3.75,0.016 3.75,3.766
  text ".Layer_Name" at 14.656,-21.806 h1.52

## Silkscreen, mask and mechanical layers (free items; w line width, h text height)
Top Overlay:
  lines w0.254: 17.2,14.75 20.2,14.75
  text "'.PRJ_Number'.PCB_Rev" at 6.5,5 h2.75 r90
  text ".Layer_Name" at 14.656,-21.806 h1.52
Bottom Overlay:
  text ".Layer_Name" at 14.656,-21.806 h1.52
Top Paste:
  text ".Layer_Name" at 14.656,-21.806 h1.52
Bottom Paste:
  text ".Layer_Name" at 14.656,-21.806 h1.52
Top Solder:
  region: 30,3.75 30,0 25,0 25,3.75
  region: 16.25,3.75 16.25,0 11.25,0 11.25,3.75
  region: 8.75,3.766 8.75,0.016 3.75,0.016 3.75,3.766
  text ".Layer_Name" at 14.656,-21.806 h1.52
  text ".Layer_Name" at 14.656,-21.806 h1.52
Bottom Solder:
  region: 30,3.75 30,0 25,0 25,3.75
  region: 16.25,3.75 16.25,0 11.25,0 11.25,3.75
  region: 8.75,3.766 8.75,0.016 3.75,0.016 3.75,3.766
  text ".Layer_Name" at 14.656,-21.806 h1.52
Drill Guide:
  text ".Layer_Name" at 14.656,-21.806 h1.52
M1 Board Outline:
  lines w0.254: 3.75,0 3.75,35 30,35 30,0 25,0 25,3 16.25,3 16.25,0 3.75,0
  text ".Layer_Name" at 14.656,-21.806 h1.52
M2 Board Dimensions:
  rectangle: 0,-6.985 3.175,-3.81
  rectangle: 3.175,-10.16 12.7,-6.985
  lines w0.178: 0,-6.985 25.4,-6.985 ; 3.175,-10.16 3.175,-3.81 ; 6.35,-10.16 6.35,-3.81 ; 12.7,-10.16 12.7,-3.81 ; 19.05,-10.16 19.05,-3.81 ; 0,-10.16 25.4,-10.16 25.4,-3.81 0,-3.81 0,-10.16
  text ".Layer_Name" at 14.656,-21.806 h1.52
M3 3D STEP Top:
  text ".Layer_Name" at 14.656,-21.806 h1.52
M4 3D STEP Bottom:
  text ".Layer_Name" at 14.656,-21.806 h1.52
M5 Assembly Top:
  lines w0.254: -7.417,-23.626 160.223,-23.626 ; -7.417,-18.462 160.274,-18.462 ; -7.417,-13.297 -7.417,-28.791 94.31,-28.791 160.274,-28.791 160.274,-13.297 -7.404,-13.297 -7.404,-28.791 32.614,-28.791 ; 55.194,-28.791 55.194,-13.297 ; 87.376,-18.462 87.376,-13.297 ; 108.712,-18.462 108.712,-13.297 ; 124.511,-28.956 124.511,-23.804
  text "COMPONENTS MARKED 'DNP' SHOULD NOT BE POPULATED." at 29.299,-8.09 h1.52
  text "ASSEMBLY VARIANT:" at 29.286,-11.024 h1.52
  text ".VariantName" at 55.601,-11.024 h1.52
  text "PCB VIEWED FROM TOP SIDE" at -5.804,-16.654 h1.52
  text "BOARD #:" at 57.099,-16.654 h1.52
  text ".PRJ_Number" at 70.955,-16.654 h1.52
  text "REV:" at 92.405,-16.654 h1.52
  text ".PCB_Rev" at 99.809,-16.654 h1.52
  text "SVN REV:" at 113.69,-16.654 h1.52
  text ".VersionControl_RevNumber" at 126.543,-16.654 h1.52
  text "TID #:" at 57.099,-21.819 h1.52
  text ".TID" at 70.955,-21.819 h1.52
  text "PLOT NAME =" at -5.804,-27.034 h1.52
  text ".plot_File_Name" at 14.656,-27.034 h1.52
  text "GENERATED    :" at 57.15,-27.034 h1.52
  text ".Print_Date" at 79.235,-27.034 h1.52
  text ".Print_Time" at 97.752,-27.034 h1.52
  text "TEXAS INSTRUMENTS" at 129.87,-27.034 h1.52
M6 Assembly Bottom:
  lines w0.254: -7.429,-18.474 160.261,-18.474 ; -7.379,-23.639 160.261,-23.639 ; 28.334,-28.969 28.334,-23.817 ; 44.133,-18.474 44.133,-13.31 ; 65.468,-18.474 65.468,-13.31 ; 97.65,-28.804 97.65,-13.31 ; 120.231,-28.804 160.249,-28.804 160.249,-13.31 -7.429,-13.31 -7.429,-28.804 58.534,-28.804 160.261,-28.804 160.261,-13.31
  text "COMPONENTS MARKED 'DNP' SHOULD NOT BE POPULATED." at 154.991,-8.077 h1.52
  text ".VariantName" at 128.473,-11.024 h1.52
  text "ASSEMBLY VARIANT:" at 154.864,-11.024 h1.52
  text ".VersionControl_RevNumber" at 26.302,-16.667 h1.52
  text "SVN REV:" at 39.154,-16.667 h1.52
  text ".PCB_Rev" at 53.035,-16.667 h1.52
  text "REV:" at 60.439,-16.667 h1.52
  text ".PRJ_Number" at 81.89,-16.667 h1.52
  text "BOARD #:" at 95.745,-16.667 h1.52
  text "PCB VIEWED FROM BOTTOM SIDE" at 158.648,-16.667 h1.52
  text ".TID" at 81.89,-21.831 h1.52
  text "TID #:" at 95.745,-21.831 h1.52
  text "TEXAS INSTRUMENTS" at 22.974,-27.047 h1.52
  text ".Print_Time" at 55.093,-27.047 h1.52
  text ".Print_Date" at 73.609,-27.047 h1.52
  text "GENERATED    :" at 95.694,-27.047 h1.52
  text ".plot_File_Name" at 138.189,-27.047 h1.52
  text "PLOT NAME =" at 158.648,-27.047 h1.52
M9 Title Sheet:
  drawing of 57 lines, arcs and shapes, not listed
  text "1" at 18.792,204.127 h1.78
  text "2" at 82.182,204.127 h1.78
  text "3" at 145.411,204.127 h1.78
  text "4" at 209.08,204.127 h1.78
  text "5" at 272.555,204.127 h1.78
  text "6" at 336.182,204.127 h1.78
  text "A" at -10.579,175.095 h1.78
  text "A" at 365.341,175.095 h1.78
  text "B" at -10.579,114.643 h1.78
  text "B" at 365.341,114.643 h1.78
  text "C" at -10.579,54.318 h1.78
  text "C" at 365.341,54.318 h1.78
  text "PROJECT TITLE:" at 288.125,7.048 h1.14
  text ".PRJ_Title" at 289.395,3.662 h1.78
  text "DESIGNED FOR:" at 288.125,-0.597 h1.14
  text ".PRJ_Customer" at 289.395,-4.153 h1.78
  text "D" at -10.579,-5.88 h1.78
  text "D" at 365.341,-5.88 h1.78
  text "FILE NAME:" at 288.125,-8.217 h1.14
  text ".PCB_File_Name_No_Path" at 289.395,-11.265 h1.78
  text "Texas Instruments (TI) and/or its licensors do not warrant the accuracy or completeness of this specification" at 161.9,-15.376 h1.14
  text "ENGINEER:" at 288.125,-15.583 h1.14
  text "LAYOUT BY:" at 326.352,-15.583 h1.14
  text "or any information contained therein. TI and/or its licensors do not warrant that this design will meet" at 160.757,-18.237 h1.14
  text ".PRJ_Engineer" at 289.395,-19.52 h1.78
  text ".PCB_Layout" at 327.635,-19.52 h1.78
  text "the specifications, will be suitable for your application or fit for any particular purpose, or will operate in" at 160.757,-21.099 h1.14
  text ".Layer_Name" at 14.656,-21.806 h1.52
  text "ALTIUM DESIGNER VERSION:" at 326.352,-23.457 h1.14
  text "an implementation. TI and/or its licensors do not warrant that the design is production worthy. You should" at 160.757,-23.961 h1.14
  text "completely validate and test your design implementation to confirm the system functionality for your application." at 161.9,-26.822 h1.14
  text ".print_Scale" at 289.395,-26.843 h1.78
  text ".Application_BuildNumber" at 327.635,-26.843 h1.78
  text "1" at 18.792,-32.093 h1.78
  text "2" at 82.182,-32.093 h1.78
  text "3" at 145.411,-32.093 h1.78
  text "4" at 209.08,-32.093 h1.78
  text "5" at 272.555,-32.093 h1.78
  text "6" at 336.182,-32.093 h1.78
M10 Fab Notes:
  drawing of 189 lines, arcs and shapes, not listed
  text "DESIGN INFORMATION" at 314.503,161.447 h1.52
  text "MIN. TRACK WIDTH:" at 298.131,158.091 h1.52
  text "8" at 325.976,158.091 h1.52
  text "MIL" at 329.907,158.091 h1.52
  text "7.874" at 321.75,155 h1.52
  text "MIN. CLEARANCE:" at 298.131,154.938 h1.52
  text "MIL" at 329.907,154.938 h1.52
  text "MIN. VIA PAD SIZE:" at 298.131,151.785 h1.52
  text "24" at 325.214,151.785 h1.52
  text "MIL" at 329.907,151.785 h1.52
  text "0.05mm (2MIL)" at 315.784,148.486 h1.52
  text "MINIMUM ANNULAR RING" at 289.769,148.277 h1.52
  text "EXTERNAL" at 333.768,148.277 h1.52
  text "PER" at 294.849,145.48 h1.52
  text "IPC-D-275 CLASS 2 LEVEL C" at 300.437,145.48 h1.52
  text "MIL, HOLES" at 338.238,142.928 h1.52
  text "+/-" at 328.27,142.709 h1.52
  text "+/-" at 349.961,142.709 h1.52
  text "REGISTRATION TOLERANCES:" at 289.769,142.682 h1.52
  text "METAL" at 320.243,142.682 h1.52
  text "5" at 334.879,142.683 h1.52
  text "3" at 356.037,142.683 h1.52
  text "MIL" at 358.99,142.682 h1.52
  text "HOLE SIZE TOLERANCE (UNLESS OTHERWISE SPECIFIED):" at 289.769,140.185 h1.52
  text "+/-" at 349.961,140.112 h1.52
  text "3" at 356.037,140.085 h1.52
  text "MIL" at 358.99,140.085 h1.52
  text "MATERIAL:" at 287.87,136.589 h1.52
  text "FR-4 High Tg" at 312.926,133.324 h1.52
  text "X" at 309.257,133.122 h1.52
  text "FR-408" at 298.563,133.007 h1.52
  text "OTHER" at 336.358,133.007 h1.52
  text "62 MIL (1.6mm) +/-10%" at 306.694,129.374 h1.52
  text "X" at 303.643,129.312 h1.52
  text "THICKNESS:" at 289.769,129.165 h1.52
  text "OTHER" at 339.33,129.165 h1.52
  text "TOLERANCE:" at 289.769,125.652 h1.52
  text "X" at 311.314,125.652 h1.52
  text "ANSI IPC-6012 TYPE 3 CLASS 2" at 315.836,125.652 h1.52
  text "OTHER +/-" at 315.835,121.989 h1.52
  text "BOW & TWIST:" at 289.769,118.302 h1.52
  text "X" at 311.314,118.302 h1.52
  text "ANSI IPC-6012 TYPE 3 CLASS 2" at 315.836,118.302 h1.52
  text "OTHER +/-" at 315.835,114.576 h1.52
  text "DRILLING:" at 287.87,111.258 h1.52
  text "NC_DRILL FILES" at 332.599,108.586 h1.52
  text "REFERENCE:" at 289.769,108.486 h1.52
  text "X" at 306.463,108.484 h1.52
  text "AS SHOWN" at 310.984,108.486 h1.52
  text "X" at 329.348,108.486 h1.52
  text "OTHER" at 340.168,104.873 h1.52
  text "PTH COPPER THICKNESS:" at 289.761,104.783 h1.52
  text "X" at 318.697,104.783 h1.52
  text "20-30 um" at 321.948,104.783 h1.52
  text "BOARD FINISH:" at 287.87,101.034 h1.52
  text "SILKSCREEN:" at 291.812,98.237 h1.52
  text "X" at 316.14,98.237 h1.52
  text "TOP" at 319.112,98.237 h1.52
  text "X" at 329.094,98.237 h1.52
  text "BOTTOM" at 332.091,98.237 h1.52
  text "SILKSCREEN COLOR:" at 291.812,94.295 h1.52
  text "X" at 316.115,94.295 h1.52
  text "WHITE" at 319.112,94.295 h1.52
  text "OTHER" at 332.091,94.295 h1.52
  text "X" at 319.442,90.652 h1.52
  text "GREEN" at 322.439,90.652 h1.52
  text "OTHER" at 338.136,90.652 h1.52
  text "SOLDER RESIST COLOR:" at 291.812,90.477 h1.52
  text "X" at 319.442,86.734 h1.52
  text "MATTE" at 322.439,86.734 h1.52
  text "SEMI-GLOSS" at 338.125,86.717 h1.52
  text "IMMERSION GOLD (ENIG)" at 314.819,82.345 h1.52
  text "ENEPIG" at 348.793,82.162 h1.52
  text "SURFACE FINISH:" at 287.87,82.136 h1.52
  text "X" at 310.298,82.136 h1.52
  text "IMM. TIN/SILVER OR EQUIV" at 296.24,78.649 h1.52
  text "OTHER" at 332.599,78.549 h1.52
  text "ARRAY/PANEL:" at 287.87,74.602 h1.52
  text "CUT AND TRIM PER M1 BOARD OUTLINE" at 314.819,74.393 h1.52
  text "N.C. ROUTE" at 314.819,70.94 h1.52
  text "X" at 332.295,70.94 h1.52
  text "V. SCORE" at 336.816,70.94 h1.52
  text "CERTIFICATION:" at 287.87,67.66 h1.52
  text "MATERIALS AND WORKMANSHIP FOR ALL PCBS" at 306.285,67.66 h1.52
  text "TO MEET OR EXCEED THE REQUIREMENTS OF:" at 306.285,65.271 h1.52
  text "X" at 297.078,62.003 h1.52
  text "ANSI IPC-A-600F CLASS ->" at 300.329,62.003 h1.52
  text "X" at 342.188,62.003 h1.52
  text "2" at 344.982,62.003 h1.52
  text "1" at 336.981,61.965 h1.52
  text "3" at 353.973,61.965 h1.52
  text "X" at 317.702,58.252 h1.52
  text "RoHS" at 320.953,58.252 h1.52
  text "OTHER" at 337.321,58.252 h1.52
  text "PER ORDER" at 347.407,58.252 h1.52
  text "ALL BOARDS MUST MEET OR EXCEED UL94-V0 REQUIREMENTS." at 288.569,54.345 h1.52
  text "PCB MUST BEAR THE UL94V-0 UL REGISTERED MATERIAL ID NUMBER" at 288.569,51.397 h1.52
  text "ADDITIONAL REQUIREMENTS:" at 287.87,47.094 h1.52
  text "MICROSECTION:" at 289.769,44.373 h1.52
  text "YES" at 312.775,44.373 h1.52
  text "REQUIRED" at 334.657,40.707 h1.52
  text "BARE BOARD ELEC. TEST:" at 289.769,40.634 h1.52
  text "NONE" at 322.935,40.634 h1.52
  text "X" at 331.66,40.634 h1.52
  text "PER ORDER" at 349.693,40.634 h1.52
  text "XX MIL VIAS REQUIRE NON-CONDUCTIVE FILL AND PLANARIZE" at 294.04,35.428 h1.5
  text "XX MIL VIAS REQUIRE CONDUCTIVE FILL AND PLANARIZE" at 294.243,32.787 h1.52
  text "OUTER XX MIL TRACES REQUIRE 50 OHM SINGLE-ENDED IMPEDANCE" at 294.218,28.637 h1.47
  text "LAYER 2 & 3 (INNER LAYERS) XX MIL WIDE, XX MIL SPACE / TRACES REQUIRE 100 OHM DIFFERENTIAL IMPEDANCE" at 294.015,22.65 h1.52
  text ".Layer_Name" at 14.656,-21.806 h1.52
M11 Gerber Information:
  lines w0.254: -7.417,-23.626 160.223,-23.626 ; -7.417,-18.462 160.274,-18.462 ; -7.417,-13.297 -7.417,-28.791 94.31,-28.791 160.274,-28.791 160.274,-13.297 -7.404,-13.297 -7.404,-28.791 32.614,-28.791 ; 55.194,-28.791 55.194,-13.297 ; 87.376,-18.462 87.376,-13.297 ; 108.712,-18.462 108.712,-13.297 ; 124.511,-28.956 124.511,-23.804
  text "ALL ARTWORK VIEWED FROM TOP SIDE" at -5.804,-16.654 h1.52
  text "BOARD #:" at 57.099,-16.654 h1.52
  text ".PRJ_Number" at 70.955,-16.654 h1.52
  text "REV:" at 92.405,-16.654 h1.52
  text ".PCB_Rev" at 99.809,-16.654 h1.52
  text "SVN REV:" at 113.69,-16.654 h1.52
  text ".VersionControl_RevNumber" at 126.543,-16.654 h1.52
  text "LAYER NAME =" at -5.804,-21.806 h1.52
  text "TID #:" at 57.099,-21.819 h1.52
  text ".TID" at 70.955,-21.819 h1.52
  text "PLOT NAME =" at -5.804,-27.034 h1.52
  text ".plot_File_Name" at 14.656,-27.034 h1.52
  text "GENERATED    :" at 57.15,-27.034 h1.52
  text ".Print_Date" at 79.235,-27.034 h1.52
  text ".Print_Time" at 97.752,-27.034 h1.52
  text "TEXAS INSTRUMENTS" at 129.87,-27.034 h1.52
M12 Stackup:
  drawing of 339 lines, arcs and shapes, not listed
  text "Layer" at 213.338,189.288 h1.52
  text "Name" at 223.75,189.288 h1.52
  text "Material" at 247.366,189.288 h1.52
  text "Thickness" at 269.204,189.288 h1.52
  text "Constant" at 285.709,189.288 h1.52
  text "Board Layer Stack" at 300.184,189.288 h1.52
  text "Board Layer Stack" at 328.624,189.288 h1.52
  text "1" at 213.338,186.24 h1.52
  text "Top Overlay" at 223.75,186.24 h1.52
  text "2" at 213.338,183.192 h1.52
  text "Top Solder" at 223.75,183.192 h1.52
  text "Solder Resist" at 247.366,183.192 h1.52
  text "0.40mil" at 269.204,183.192 h1.52
  text "3.5" at 285.709,183.192 h1.52
  text "3" at 213.338,180.144 h1.52
  text "Top Layer" at 223.75,180.144 h1.52
  text "Copper" at 247.366,180.144 h1.52
  text "1.40mil" at 269.204,180.144 h1.52
  text "4" at 213.338,177.096 h1.52
  text "Dielectric1" at 223.75,177.096 h1.52
  text "FR-4 High Tg" at 247.366,177.096 h1.52
  text "59.20mil" at 269.204,177.096 h1.52
  text "4.8" at 285.709,177.096 h1.52
  text "5" at 213.338,174.048 h1.52
  text "Bottom Layer" at 223.75,174.048 h1.52
  text "Copper" at 247.366,174.048 h1.52
  text "1.40mil" at 269.204,174.048 h1.52
  text "6" at 213.338,171 h1.52
  text "Bottom Solder" at 223.75,171 h1.52
  text "Solder Resist" at 247.366,171 h1.52
  text "0.40mil" at 269.204,171 h1.52
  text "3.5" at 285.709,171 h1.52
  text "7" at 213.338,167.952 h1.52
  text "Bottom Overlay" at 223.75,167.952 h1.52
  text ".Layer_Name" at 14.656,-21.806 h1.52
M13 Component Bodies Top:
  text ".Layer_Name" at 14.656,-21.806 h1.52
M14 Component Bodies Bottom:
  text ".Layer_Name" at 14.656,-21.806 h1.52
M15 Courtyards Top:
  text ".Layer_Name" at 14.656,-21.806 h1.52
M16 Courtyards Bottom:
  text ".Layer_Name" at 14.656,-21.806 h1.52
Drill Drawing:
  lines w0.254: 135.537,78.566 135.888,78.566 135.888,78.215 136.589,78.215 136.589,78.566 136.94,78.566 136.94,79.268 136.589,79.268 136.589,79.619 135.888,79.619 135.888,79.268 135.537,79.268 135.537,78.566 ; 135.537,81.724 135.888,81.724 136.238,81.373 136.589,81.724 136.94,81.724 136.589,82.075 136.94,82.425 136.589,82.425 136.238,82.776 135.888,82.425 135.537,82.425 135.888,82.075 135.537,81.724 ; 135.537,84.531 136.94,84.531 136.94,85.934 135.537,85.934 135.537,84.531
  lines w0.305: 134.264,77.268 216.344,77.268 ; 134.264,86.741 216.344,86.741 ; 142.846,74.11 142.846,89.899 ; 151.279,74.11 151.279,89.899 ; 167.448,74.11 167.448,89.899 ; 174.03,74.11 174.03,89.899 ; 183.559,74.11 183.559,89.899 ; 201.957,74.11 201.957,89.899 ; 134.264,74.11 216.344,74.11 216.344,89.899 134.264,89.899 134.264,74.11
  text "Symbol" at 136.159,87.688 h1.83
  text "Quantity" at 143.793,87.688 h1.83
  text "Finished Hole Size" at 152.226,87.688 h1.83
  text "Plated" at 168.395,87.688 h1.83
  text "Hole Type" at 174.977,87.688 h1.83
  text "Drill Layer Pair" at 184.506,87.688 h1.83
  text "Hole Tolerance" at 202.904,87.688 h1.83
  text "48" at 143.793,84.531 h1.52
  text "10.00mil (0.254mm)" at 152.226,84.531 h1.52
  text "PTH" at 168.395,84.531 h1.52
  text "Round" at 174.977,84.531 h1.52
  text "Top Layer - Bottom Layer" at 184.506,84.531 h1.52
  text "2" at 143.793,81.373 h1.52
  text "43.31mil (1.100mm)" at 152.226,81.373 h1.52
  text "PTH" at 168.395,81.373 h1.52
  text "Round" at 174.977,81.373 h1.52
  text "Top Layer - Bottom Layer" at 184.506,81.373 h1.52
  text "2" at 143.793,78.215 h1.52
  text "55.12mil (1.400mm)" at 152.226,78.215 h1.52
  text "PTH" at 168.395,78.215 h1.52
  text "Round" at 174.977,78.215 h1.52
  text "Top Layer - Bottom Layer" at 184.506,78.215 h1.52
  text "52 Total" at 143.793,75.057 h1.52
  text ".Layer_Name" at 14.656,-21.806 h1.52
M17 Embedded Cavity:
  text ".Layer_Name" at 14.656,-21.806 h1.52
M18 Embedded Assembly:
  text ".Layer_Name" at 14.656,-21.806 h1.52
M19 Embedded Keepout:
  text ".Layer_Name" at 14.656,-21.806 h1.52

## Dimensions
0,-10.16 to 25.4,-10.16 on M2 Board Dimensions
3.75,0 to 3.75,35 on M2 Board Dimensions
30,0 to 3.75,0 on M2 Board Dimensions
